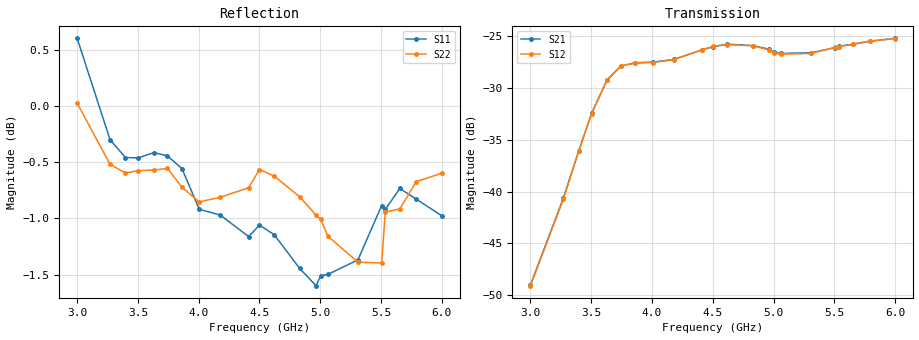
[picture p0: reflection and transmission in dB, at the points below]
!  26/11/2025  16:22:48
! Ref Plane: 0.000 mm
# MHZ S MA R  50
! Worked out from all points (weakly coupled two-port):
!   401 points, 3 GHz to 6 GHz, reference 50 ohm
!   highest |S21| = -25.20 dB at 6 GHz (marker M1); lowest = -49.0 dB at 3 GHz (marker M2)
!   lowest |S11| = -1.6 dB at 4.965 GHz (marker M3), VSWR 10.90, Z = 10 - j54 ohm
!   |S11| at or under -10 dB: nowhere
!   |S22| runs from -1.4 to 0.1 dB; largest |S21 - S12| = 0.0023
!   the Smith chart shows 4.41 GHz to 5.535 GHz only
!   S11 on the Smith chart (normalised r, x): 4.41 GHz: 0.13, +0.96; 4.62 GHz: 1.33, +4.19; 4.83 GHz: 0.61, -2.46; 5.062 GHz: 0.12, -0.66; 5.31 GHz: 0.08, +0.01; 5.535 GHz: 0.07, +0.63
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3000  1.072 -137.6  0.003532 47.4  0.003506 50.5  1.003 -106.7
3270  0.9663 152.1  0.009274 -19.4  0.009159 -16.1  0.9422 -171.5
3397.5  0.9487 108.9  0.01573 -59.0  0.01574 -57.9  0.9337 149.9
3502.5  0.9484 66.3  0.02383 -99.2  0.0237 -97.9  0.9361 112.1
3630  0.9535 11.3  0.03458 -155.1  0.03466 -153.9  0.9366 56.9
3742.5  0.9504 -38.3  0.04039 154.7  0.04034 156.2  0.9382 8.4
3862.5  0.9379 -86.2  0.04183 105.5  0.04199 107.1  0.9202 -40.4
4005  0.8996 -137.8  0.0422 54.8  0.042 56.0  0.9065 -90.1
4177.5  0.8944 166.7  0.04347 -0.5  0.04337 1.3  0.9109 -144.4
4410  0.8749 92.0  0.04834 -73.9  0.04837 -72.2  0.9197 145.0
4500  0.8851 63.8  0.05008 -102.8  0.05028 -101.2  0.9371 117.2
4620  0.8767 24.6  0.05152 -141.6  0.0513 -140.4  0.9309 79.4
4830  0.8468 -42.1  0.05074 151.6  0.05058 153.2  0.9113 16.4
4965  0.8319 -84.6  0.04868 111.7  0.04834 113.2  0.8944 -22.4
5002.5  0.8402 -96.1  0.04703 101.3  0.04665 102.5  0.8907 -34.1
5062.5  0.8416 -112.8  0.04646 84.7  0.04611 85.8  0.8752 -52.1
5310  0.8542 179.3  0.04684 18.9  0.04647 20.4  0.8522 -123.9
5505  0.9031 121.7  0.04959 -34.0  0.04974 -31.9  0.8515 -176.2
5535  0.8996 115.1  0.05028 -41.3  0.05021 -39.3  0.8971 177.4
5655  0.9191 80.5  0.05159 -75.6  0.05142 -73.1  0.9001 142.2
5790  0.9091 41.6  0.05321 -114.4  0.05337 -112.4  0.9255 104.3
6000  0.8937 -20.0  0.05498 -174.6  0.05484 -173.0  0.9337 50.4
